VERSION 5.7 ;
  NOWIREEXTENSIONATPIN ON ;
  DIVIDERCHAR "/" ;
  BUSBITCHARS "[]" ;
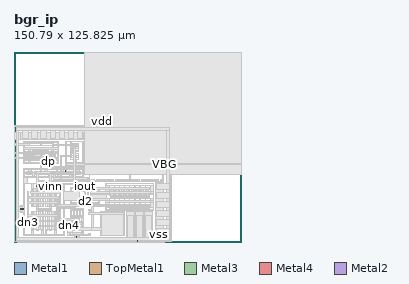
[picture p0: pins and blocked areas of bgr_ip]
MACRO bgr_ip
  CLASS BLOCK ;
  FOREIGN bgr_ip ;
  ORIGIN 58.750 13.520 ;
  SIZE 150.790 BY 125.825 ;
  PIN vss
    ANTENNAGATEAREA 13.200000 ;
    ANTENNADIFFAREA 228.791992 ;
    PORT
      LAYER Metal1 ;
        RECT 23.000 -12.945 23.300 -12.345 ;
    END
    PORT
      LAYER Metal1 ;
        RECT 30.780 -10.815 31.080 -10.215 ;
    END
    PORT
      LAYER Metal1 ;
        RECT 36.885 -10.515 37.185 -9.915 ;
    END
    PORT
      LAYER Metal1 ;
        RECT -17.380 -10.515 -17.080 -9.915 ;
    END
  END vss
  PIN vdd
    ANTENNAGATEAREA 148.000000 ;
    ANTENNADIFFAREA 272.932007 ;
    PORT
      LAYER Metal1 ;
        RECT -54.655 7.790 -52.655 8.790 ;
    END
    PORT
      LAYER TopMetal1 ;
        RECT -1.690 65.610 0.310 66.610 ;
    END
  END vdd
  PIN dn3
    ANTENNAGATEAREA 6.000000 ;
    ANTENNADIFFAREA 17.340000 ;
    PORT
      LAYER Metal1 ;
        RECT -49.535 -1.245 -49.035 -0.245 ;
    END
  END dn3
  PIN VBG
    USE ANALOG ;
    ANTENNAGATEAREA 14.400000 ;
    ANTENNADIFFAREA 11.219999 ;
    PORT
      LAYER Metal3 ;
        RECT -24.920 33.485 -24.420 33.985 ;
    END
    PORT
      LAYER Metal4 ;
        RECT 40.010 37.520 42.010 38.520 ;
    END
  END VBG
  PIN vinp
    ANTENNAGATEAREA 24.000000 ;
    ANTENNADIFFAREA 0.340000 ;
    PORT
      LAYER Metal3 ;
        RECT -43.755 23.380 -42.755 24.380 ;
    END
  END vinp
  PIN vinn
    ANTENNAGATEAREA 31.199999 ;
    ANTENNADIFFAREA 9.179999 ;
    PORT
      LAYER Metal3 ;
        RECT -34.985 22.695 -33.985 23.695 ;
    END
  END vinn
  PIN dn4
    ANTENNAGATEAREA 24.000000 ;
    ANTENNADIFFAREA 17.340000 ;
    PORT
      LAYER Metal3 ;
        RECT -22.745 -3.400 -22.245 -2.400 ;
    END
  END dn4
  PIN d2
    ANTENNADIFFAREA 36.719997 ;
    PORT
      LAYER Metal3 ;
        RECT -11.955 12.835 -11.455 13.335 ;
    END
  END d2
  PIN iout
    ANTENNAGATEAREA 324.000000 ;
    ANTENNADIFFAREA 9.120000 ;
    PORT
      LAYER Metal2 ;
        RECT -12.205 22.745 -11.205 23.245 ;
    END
  END iout
  PIN dp
    ANTENNAGATEAREA 14.400000 ;
    ANTENNADIFFAREA 11.219999 ;
    PORT
      LAYER Metal4 ;
        RECT -36.180 39.600 -35.680 40.100 ;
    END
  END dp
  PIN vout
    ANTENNAGATEAREA 22.000000 ;
    ANTENNADIFFAREA 17.080000 ;
    PORT
      LAYER Metal4 ;
        RECT -8.955 10.310 -7.955 10.810 ;
    END
  END vout
  OBS
      LAYER GatPoly ;
        RECT -7.555 57.935 -6.805 58.365 ;
        RECT -5.985 57.935 -5.235 58.365 ;
        RECT -4.415 57.935 -3.665 58.365 ;
        RECT -2.845 57.935 -2.095 58.365 ;
        RECT -1.275 57.935 -0.525 58.365 ;
        RECT 0.295 57.935 1.045 58.365 ;
        RECT 1.865 57.935 2.615 58.365 ;
        RECT 3.435 57.935 4.185 58.365 ;
        RECT 5.005 57.935 5.755 58.365 ;
        RECT 6.575 57.935 7.325 58.365 ;
        RECT 8.145 57.935 8.895 58.365 ;
        RECT 9.715 57.935 10.465 58.365 ;
        RECT 11.285 57.935 12.035 58.365 ;
        RECT 12.855 57.935 13.605 58.365 ;
        RECT 14.425 57.935 15.175 58.365 ;
        RECT 15.995 57.935 16.745 58.365 ;
        RECT 17.565 57.935 18.315 58.365 ;
        RECT 19.135 57.935 19.885 58.365 ;
        RECT 20.705 57.935 21.455 58.365 ;
        RECT 22.275 57.935 23.025 58.365 ;
        RECT 23.845 57.935 24.595 58.365 ;
        RECT 25.415 57.935 26.165 58.365 ;
        RECT 26.985 57.935 27.735 58.365 ;
        RECT 28.555 57.935 29.305 58.365 ;
        RECT 30.125 57.935 30.875 58.365 ;
        RECT 31.695 57.935 32.445 58.365 ;
        RECT 33.265 57.935 34.015 58.365 ;
        RECT 34.835 57.935 35.585 58.365 ;
        RECT 36.405 57.935 37.155 58.365 ;
        RECT 37.975 57.935 38.725 58.365 ;
        RECT -46.095 51.720 -44.095 52.020 ;
        RECT -37.875 51.720 -35.875 52.020 ;
        RECT -48.595 51.540 -41.595 51.720 ;
        RECT -40.375 51.540 -33.375 51.720 ;
        RECT -48.595 50.360 -41.595 50.540 ;
        RECT -40.375 50.360 -33.375 50.540 ;
        RECT -21.595 49.970 -21.195 50.970 ;
        RECT -16.195 50.790 -15.795 50.970 ;
        RECT -16.195 50.150 -15.715 50.790 ;
        RECT -16.195 49.970 -15.795 50.150 ;
        RECT -21.595 48.050 -21.375 49.970 ;
        RECT -16.015 48.050 -15.795 49.970 ;
        RECT -21.595 47.050 -21.195 48.050 ;
        RECT -16.195 47.050 -15.795 48.050 ;
        RECT -51.025 46.360 -50.725 46.455 ;
        RECT -41.305 46.360 -40.665 47.000 ;
        RECT -31.245 46.360 -30.945 46.455 ;
        RECT -51.025 45.910 -50.545 46.360 ;
        RECT -46.545 45.910 -46.365 46.360 ;
        RECT -45.685 45.910 -45.505 46.360 ;
        RECT -41.505 45.910 -40.465 46.360 ;
        RECT -36.465 45.910 -36.285 46.360 ;
        RECT -35.605 45.910 -35.425 46.360 ;
        RECT -31.425 45.910 -30.945 46.360 ;
        RECT -51.025 45.815 -50.725 45.910 ;
        RECT -31.245 45.815 -30.945 45.910 ;
        RECT -51.025 44.240 -50.545 44.690 ;
        RECT -46.545 44.240 -46.365 44.690 ;
        RECT -45.685 44.240 -45.505 44.690 ;
        RECT -41.505 44.240 -40.465 44.690 ;
        RECT -36.465 44.240 -36.285 44.690 ;
        RECT -35.605 44.240 -35.425 44.690 ;
        RECT -31.425 44.240 -30.945 44.690 ;
        RECT -51.025 43.020 -50.725 44.240 ;
        RECT -41.210 43.950 -40.760 44.240 ;
        RECT -41.305 43.310 -40.665 43.950 ;
        RECT -41.210 43.020 -40.760 43.310 ;
        RECT -31.245 43.020 -30.945 44.240 ;
        RECT -51.025 42.570 -50.545 43.020 ;
        RECT -46.545 42.570 -46.365 43.020 ;
        RECT -45.685 42.570 -45.505 43.020 ;
        RECT -41.505 42.570 -40.465 43.020 ;
        RECT -36.465 42.570 -36.285 43.020 ;
        RECT -35.605 42.570 -35.425 43.020 ;
        RECT -31.425 42.570 -30.945 43.020 ;
        RECT -21.595 44.130 -21.195 45.130 ;
        RECT -16.195 44.130 -15.795 45.130 ;
        RECT -21.595 43.450 -21.375 44.130 ;
        RECT -21.595 42.810 -20.525 43.450 ;
        RECT -21.595 42.210 -21.375 42.810 ;
        RECT -16.015 42.210 -15.795 44.130 ;
        RECT -7.555 43.005 -6.805 43.435 ;
        RECT -5.985 43.005 -5.235 43.435 ;
        RECT -4.415 43.005 -3.665 43.435 ;
        RECT -2.845 43.005 -2.095 43.435 ;
        RECT -1.275 43.005 -0.525 43.435 ;
        RECT 0.295 43.005 1.045 43.435 ;
        RECT 1.865 43.005 2.615 43.435 ;
        RECT 3.435 43.005 4.185 43.435 ;
        RECT 5.005 43.005 5.755 43.435 ;
        RECT 6.575 43.005 7.325 43.435 ;
        RECT 8.145 43.005 8.895 43.435 ;
        RECT 9.715 43.005 10.465 43.435 ;
        RECT 11.285 43.005 12.035 43.435 ;
        RECT 12.855 43.005 13.605 43.435 ;
        RECT 14.425 43.005 15.175 43.435 ;
        RECT 15.995 43.005 16.745 43.435 ;
        RECT 17.565 43.005 18.315 43.435 ;
        RECT 19.135 43.005 19.885 43.435 ;
        RECT 20.705 43.005 21.455 43.435 ;
        RECT 22.275 43.005 23.025 43.435 ;
        RECT 23.845 43.005 24.595 43.435 ;
        RECT 25.415 43.005 26.165 43.435 ;
        RECT 26.985 43.005 27.735 43.435 ;
        RECT 28.555 43.005 29.305 43.435 ;
        RECT 30.125 43.005 30.875 43.435 ;
        RECT 31.695 43.005 32.445 43.435 ;
        RECT 33.265 43.005 34.015 43.435 ;
        RECT 34.835 43.005 35.585 43.435 ;
        RECT 36.405 43.005 37.155 43.435 ;
        RECT 37.975 43.005 38.725 43.435 ;
        RECT -7.555 42.215 -6.805 42.645 ;
        RECT -5.985 42.215 -5.235 42.645 ;
        RECT -4.415 42.215 -3.665 42.645 ;
        RECT -2.845 42.215 -2.095 42.645 ;
        RECT -1.275 42.215 -0.525 42.645 ;
        RECT 0.295 42.215 1.045 42.645 ;
        RECT 1.865 42.215 2.615 42.645 ;
        RECT 3.435 42.215 4.185 42.645 ;
        RECT 5.005 42.215 5.755 42.645 ;
        RECT 6.575 42.215 7.325 42.645 ;
        RECT 8.145 42.215 8.895 42.645 ;
        RECT 9.715 42.215 10.465 42.645 ;
        RECT 11.285 42.215 12.035 42.645 ;
        RECT 12.855 42.215 13.605 42.645 ;
        RECT 14.425 42.215 15.175 42.645 ;
        RECT 15.995 42.215 16.745 42.645 ;
        RECT 17.565 42.215 18.315 42.645 ;
        RECT 19.135 42.215 19.885 42.645 ;
        RECT 20.705 42.215 21.455 42.645 ;
        RECT 22.275 42.215 23.025 42.645 ;
        RECT 23.845 42.215 24.595 42.645 ;
        RECT 25.415 42.215 26.165 42.645 ;
        RECT 26.985 42.215 27.735 42.645 ;
        RECT 28.555 42.215 29.305 42.645 ;
        RECT 30.125 42.215 30.875 42.645 ;
        RECT 31.695 42.215 32.445 42.645 ;
        RECT 33.265 42.215 34.015 42.645 ;
        RECT 34.835 42.215 35.585 42.645 ;
        RECT 36.405 42.215 37.155 42.645 ;
        RECT 37.975 42.215 38.725 42.645 ;
        RECT -51.025 41.350 -50.725 41.445 ;
        RECT -31.245 41.350 -30.945 41.445 ;
        RECT -51.025 40.900 -50.545 41.350 ;
        RECT -46.545 40.900 -46.365 41.350 ;
        RECT -45.685 40.900 -45.505 41.350 ;
        RECT -41.505 40.900 -40.465 41.350 ;
        RECT -36.465 40.900 -36.285 41.350 ;
        RECT -35.605 40.900 -35.425 41.350 ;
        RECT -31.425 40.900 -30.945 41.350 ;
        RECT -21.595 41.210 -21.195 42.210 ;
        RECT -16.195 41.210 -15.795 42.210 ;
        RECT -51.025 40.805 -50.725 40.900 ;
        RECT -41.305 40.260 -40.665 40.900 ;
        RECT -31.245 40.805 -30.945 40.900 ;
        RECT -49.455 32.860 -47.455 33.500 ;
        RECT -38.855 32.860 -36.855 33.500 ;
        RECT -28.255 32.860 -26.255 33.500 ;
        RECT -17.655 32.860 -15.655 33.500 ;
        RECT -50.455 32.680 -46.455 32.860 ;
        RECT -45.155 32.680 -41.155 32.860 ;
        RECT -39.855 32.680 -35.855 32.860 ;
        RECT -34.555 32.680 -30.555 32.860 ;
        RECT -29.255 32.680 -25.255 32.860 ;
        RECT -23.955 32.680 -19.955 32.860 ;
        RECT -18.655 32.680 -14.655 32.860 ;
        RECT -50.455 31.500 -46.455 31.680 ;
        RECT -45.155 31.500 -41.155 31.680 ;
        RECT -39.855 31.500 -35.855 31.680 ;
        RECT -34.555 31.500 -30.555 31.680 ;
        RECT -29.255 31.500 -25.255 31.680 ;
        RECT -23.955 31.500 -19.955 31.680 ;
        RECT -18.655 31.500 -14.655 31.680 ;
        RECT -44.155 30.860 -42.155 31.500 ;
        RECT -33.555 30.860 -31.555 31.500 ;
        RECT -22.955 30.860 -20.955 31.500 ;
        RECT -7.555 27.285 -6.805 27.715 ;
        RECT -5.985 27.285 -5.235 27.715 ;
        RECT -4.415 27.285 -3.665 27.715 ;
        RECT -2.845 27.285 -2.095 27.715 ;
        RECT -1.275 27.285 -0.525 27.715 ;
        RECT 0.295 27.285 1.045 27.715 ;
        RECT 1.865 27.285 2.615 27.715 ;
        RECT 3.435 27.285 4.185 27.715 ;
        RECT 5.005 27.285 5.755 27.715 ;
        RECT 6.575 27.285 7.325 27.715 ;
        RECT 8.145 27.285 8.895 27.715 ;
        RECT 9.715 27.285 10.465 27.715 ;
        RECT 11.285 27.285 12.035 27.715 ;
        RECT 12.855 27.285 13.605 27.715 ;
        RECT 14.425 27.285 15.175 27.715 ;
        RECT 15.995 27.285 16.745 27.715 ;
        RECT 17.565 27.285 18.315 27.715 ;
        RECT 19.135 27.285 19.885 27.715 ;
        RECT 20.705 27.285 21.455 27.715 ;
        RECT 22.275 27.285 23.025 27.715 ;
        RECT 23.845 27.285 24.595 27.715 ;
        RECT 25.415 27.285 26.165 27.715 ;
        RECT 26.985 27.285 27.735 27.715 ;
        RECT 28.555 27.285 29.305 27.715 ;
        RECT 30.125 27.285 30.875 27.715 ;
        RECT 31.695 27.285 32.445 27.715 ;
        RECT 33.265 27.285 34.015 27.715 ;
        RECT 34.835 27.285 35.585 27.715 ;
        RECT 36.405 27.285 37.155 27.715 ;
        RECT 37.975 27.285 38.725 27.715 ;
        RECT 4.615 23.640 7.615 23.820 ;
        RECT 7.995 23.640 10.995 23.820 ;
        RECT 11.375 23.640 14.375 23.820 ;
        RECT 14.755 23.640 17.755 23.820 ;
        RECT 18.135 23.640 21.135 23.820 ;
        RECT 21.515 23.640 24.515 23.820 ;
        RECT 24.895 23.640 27.895 23.820 ;
        RECT 28.275 23.640 31.275 23.820 ;
        RECT -46.645 22.095 -45.665 22.735 ;
        RECT -40.805 22.095 -39.825 22.735 ;
        RECT -37.885 22.095 -36.905 22.735 ;
        RECT -32.045 22.095 -31.065 22.735 ;
        RECT -46.655 21.915 -45.655 22.095 ;
        RECT -43.735 21.915 -42.735 22.095 ;
        RECT -40.815 21.915 -39.815 22.095 ;
        RECT -37.895 21.915 -36.895 22.095 ;
        RECT -34.975 21.915 -33.975 22.095 ;
        RECT -32.055 21.915 -31.055 22.095 ;
        RECT -12.715 20.950 -10.715 21.045 ;
        RECT -18.775 20.405 -16.775 20.705 ;
        RECT -15.235 20.405 -8.195 20.950 ;
        RECT -6.655 20.405 -4.655 20.705 ;
        RECT -19.275 20.225 -16.275 20.405 ;
        RECT -15.235 20.225 -12.235 20.405 ;
        RECT -11.195 20.225 -8.195 20.405 ;
        RECT -7.155 20.225 -4.155 20.405 ;
        RECT 4.615 17.460 7.615 17.640 ;
        RECT 7.995 17.460 10.995 17.640 ;
        RECT 11.375 17.460 14.375 17.640 ;
        RECT 14.755 17.460 17.755 17.640 ;
        RECT 18.135 17.460 21.135 17.640 ;
        RECT 21.515 17.460 24.515 17.640 ;
        RECT 24.895 17.460 27.895 17.640 ;
        RECT 28.275 17.460 31.275 17.640 ;
        RECT 5.115 16.890 7.115 17.460 ;
        RECT 8.495 16.890 10.495 17.460 ;
        RECT 11.875 16.890 13.875 17.460 ;
        RECT 15.255 16.890 17.255 17.460 ;
        RECT 18.635 16.890 20.635 17.460 ;
        RECT 22.015 16.890 24.015 17.460 ;
        RECT 25.395 16.890 27.395 17.460 ;
        RECT 28.775 16.890 30.775 17.460 ;
        RECT 5.115 15.230 7.115 15.870 ;
        RECT 8.495 15.230 10.495 15.870 ;
        RECT 11.875 15.230 13.875 15.870 ;
        RECT 15.255 15.230 17.255 15.870 ;
        RECT 18.635 15.230 20.635 15.870 ;
        RECT 22.015 15.230 24.015 15.870 ;
        RECT 25.395 15.230 27.395 15.870 ;
        RECT 28.775 15.230 30.775 15.870 ;
        RECT 4.615 15.050 7.615 15.230 ;
        RECT 7.995 15.050 10.995 15.230 ;
        RECT 11.375 15.050 14.375 15.230 ;
        RECT 14.755 15.050 17.755 15.230 ;
        RECT 18.135 15.050 21.135 15.230 ;
        RECT 21.515 15.050 24.515 15.230 ;
        RECT 24.895 15.050 27.895 15.230 ;
        RECT 28.275 15.050 31.275 15.230 ;
        RECT -19.275 14.045 -16.275 14.225 ;
        RECT -15.235 14.045 -12.235 14.225 ;
        RECT -11.195 14.045 -8.195 14.225 ;
        RECT -7.155 14.045 -4.155 14.225 ;
        RECT -18.775 13.745 -16.775 14.045 ;
        RECT -15.235 13.500 -8.195 14.045 ;
        RECT -6.655 13.745 -4.655 14.045 ;
        RECT -46.655 9.735 -45.655 9.915 ;
        RECT -43.735 9.735 -42.735 9.915 ;
        RECT -40.815 9.735 -39.815 9.915 ;
        RECT -37.895 9.735 -36.895 9.915 ;
        RECT -34.975 9.735 -33.975 9.915 ;
        RECT -32.055 9.735 -31.055 9.915 ;
        RECT -43.725 9.095 -42.745 9.735 ;
        RECT -34.965 9.095 -33.985 9.735 ;
        RECT 4.615 8.870 7.615 9.050 ;
        RECT 7.995 8.870 10.995 9.050 ;
        RECT 11.375 8.870 14.375 9.050 ;
        RECT 14.755 8.870 17.755 9.050 ;
        RECT 18.135 8.870 21.135 9.050 ;
        RECT 21.515 8.870 24.515 9.050 ;
        RECT 24.895 8.870 27.895 9.050 ;
        RECT 28.275 8.870 31.275 9.050 ;
        RECT -20.425 7.315 -19.445 7.615 ;
        RECT -18.530 7.570 -17.890 7.590 ;
        RECT -18.530 7.315 -15.640 7.570 ;
        RECT -14.725 7.315 -13.745 7.615 ;
        RECT -9.090 7.430 -8.090 7.860 ;
        RECT -43.725 6.645 -42.745 7.285 ;
        RECT -34.965 6.645 -33.985 7.285 ;
        RECT -20.435 7.135 -19.435 7.315 ;
        RECT -18.530 7.135 -17.530 7.315 ;
        RECT -16.640 7.135 -15.640 7.315 ;
        RECT -14.735 7.135 -13.735 7.315 ;
        RECT -46.655 6.465 -45.655 6.645 ;
        RECT -43.735 6.465 -42.735 6.645 ;
        RECT -40.815 6.465 -39.815 6.645 ;
        RECT -37.895 6.465 -36.895 6.645 ;
        RECT -34.975 6.465 -33.975 6.645 ;
        RECT -32.055 6.465 -31.055 6.645 ;
        RECT -20.435 3.955 -19.435 4.135 ;
        RECT -18.530 3.955 -17.530 4.135 ;
        RECT -16.640 3.955 -15.640 4.135 ;
        RECT -14.735 3.955 -13.735 4.135 ;
        RECT -20.425 3.655 -19.445 3.955 ;
        RECT -18.530 3.700 -15.640 3.955 ;
        RECT -14.725 3.655 -13.745 3.955 ;
        RECT -20.265 -2.180 -20.085 -2.170 ;
        RECT -20.905 -3.160 -20.085 -2.180 ;
        RECT -20.265 -3.170 -20.085 -3.160 ;
        RECT -14.085 -3.170 -13.905 -2.170 ;
        RECT -20.265 -3.560 -20.085 -3.550 ;
        RECT -20.905 -4.540 -20.085 -3.560 ;
        RECT -20.265 -4.550 -20.085 -4.540 ;
        RECT -14.085 -4.550 -13.905 -3.550 ;
        RECT -20.265 -4.940 -20.085 -4.930 ;
        RECT -46.655 -5.715 -45.655 -5.535 ;
        RECT -43.735 -5.715 -42.735 -5.535 ;
        RECT -40.815 -5.715 -39.815 -5.535 ;
        RECT -37.895 -5.715 -36.895 -5.535 ;
        RECT -34.975 -5.715 -33.975 -5.535 ;
        RECT -32.055 -5.715 -31.055 -5.535 ;
        RECT -46.645 -6.355 -45.665 -5.715 ;
        RECT -40.805 -6.355 -39.825 -5.715 ;
        RECT -37.885 -6.355 -36.905 -5.715 ;
        RECT -32.045 -6.355 -31.065 -5.715 ;
        RECT -20.905 -5.920 -20.085 -4.940 ;
        RECT -20.265 -5.930 -20.085 -5.920 ;
        RECT -14.085 -5.930 -13.905 -4.930 ;
        RECT -20.265 -6.320 -20.085 -6.310 ;
        RECT -20.905 -7.300 -20.085 -6.320 ;
        RECT -20.265 -7.310 -20.085 -7.300 ;
        RECT -14.085 -7.310 -13.905 -6.310 ;
        RECT -9.090 -8.000 -8.090 -7.570 ;
      LAYER Metal1 ;
        RECT -58.750 62.785 45.370 63.445 ;
        RECT -58.750 59.055 -58.130 62.785 ;
        RECT -58.750 54.255 -53.595 59.055 ;
        RECT -9.050 58.925 39.950 59.225 ;
        RECT -58.750 51.540 -58.130 54.255 ;
        RECT -52.545 52.690 -29.425 53.290 ;
        RECT -52.545 51.540 -52.045 52.690 ;
        RECT -46.265 51.720 -40.485 52.110 ;
        RECT -37.855 51.790 -32.645 52.110 ;
        RECT -58.750 50.540 -48.705 51.540 ;
        RECT -41.485 50.540 -40.485 51.720 ;
        RECT -58.750 45.800 -58.130 50.540 ;
        RECT -52.545 49.390 -52.045 50.540 ;
        RECT -33.265 49.925 -32.645 51.790 ;
        RECT -29.925 49.390 -29.425 52.690 ;
        RECT -52.545 48.010 -29.425 49.390 ;
        RECT -52.545 45.800 -52.045 48.010 ;
        RECT -49.365 46.700 -47.725 48.010 ;
        RECT -51.065 46.470 -46.545 46.700 ;
        RECT -51.065 45.800 -50.725 46.470 ;
        RECT -46.330 46.380 -35.640 46.980 ;
        RECT -34.245 46.700 -32.395 48.010 ;
        RECT -35.425 46.470 -30.905 46.700 ;
        RECT -31.245 45.800 -30.905 46.470 ;
        RECT -29.925 45.800 -29.425 48.010 ;
        RECT -58.750 44.800 -29.425 45.800 ;
        RECT -58.750 42.460 -58.130 44.800 ;
        RECT -52.545 42.460 -52.045 44.800 ;
        RECT -50.545 43.970 -46.545 44.130 ;
        RECT -46.335 43.970 -45.715 43.980 ;
        RECT -51.025 43.290 -45.715 43.970 ;
        RECT -50.545 43.130 -46.545 43.290 ;
        RECT -46.335 43.280 -45.715 43.290 ;
        RECT -45.505 43.130 -36.465 44.130 ;
        RECT -36.255 43.970 -35.635 43.980 ;
        RECT -35.425 43.970 -31.425 44.130 ;
        RECT -36.255 43.290 -30.945 43.970 ;
        RECT -36.255 43.280 -31.425 43.290 ;
        RECT -35.425 43.130 -31.425 43.280 ;
        RECT -29.925 42.460 -29.425 44.800 ;
        RECT -58.750 41.460 -29.425 42.460 ;
        RECT -58.750 -12.895 -58.130 41.460 ;
        RECT -52.545 39.250 -52.045 41.460 ;
        RECT -51.065 40.790 -50.725 41.460 ;
        RECT -51.065 40.560 -46.545 40.790 ;
        RECT -49.365 39.250 -47.725 40.560 ;
        RECT -46.330 40.280 -35.640 40.880 ;
        RECT -31.245 40.790 -30.905 41.460 ;
        RECT -35.425 40.560 -30.905 40.790 ;
        RECT -34.260 39.250 -32.395 40.560 ;
        RECT -29.925 39.250 -29.425 41.460 ;
        RECT -52.545 38.650 -29.425 39.250 ;
        RECT -24.665 52.770 -12.725 53.270 ;
        RECT -24.665 39.410 -24.065 52.770 ;
        RECT -21.195 51.490 -20.495 52.240 ;
        RECT -21.195 51.080 -16.195 51.490 ;
        RECT -15.970 50.120 -15.760 50.820 ;
        RECT -21.195 48.160 -16.195 49.860 ;
        RECT -21.195 46.530 -16.195 46.940 ;
        RECT -21.195 45.985 -20.495 46.530 ;
        RECT -20.145 45.400 -19.445 46.195 ;
        RECT -21.195 45.240 -16.195 45.400 ;
        RECT -21.195 43.860 -16.195 44.020 ;
        RECT -21.195 42.820 -20.495 43.440 ;
        RECT -19.520 42.480 -17.510 43.860 ;
        RECT -21.195 42.320 -16.195 42.480 ;
        RECT -21.195 40.940 -16.195 41.100 ;
        RECT -19.520 39.410 -17.510 40.940 ;
        RECT -13.325 39.410 -12.725 52.770 ;
        RECT -24.665 38.910 -12.725 39.410 ;
        RECT -24.615 35.000 -21.595 38.910 ;
        RECT -15.795 35.000 -12.775 38.910 ;
        RECT -52.335 34.400 -12.775 35.000 ;
        RECT -52.335 32.680 -51.835 34.400 ;
        RECT -49.435 32.930 -47.475 34.400 ;
        RECT -38.835 33.430 -36.875 34.400 ;
        RECT -30.555 33.430 -29.775 34.400 ;
        RECT -28.235 33.430 -26.275 34.400 ;
        RECT -52.335 31.680 -50.565 32.680 ;
        RECT -52.335 29.960 -51.835 31.680 ;
        RECT -46.345 29.960 -45.265 32.680 ;
        RECT -41.275 31.680 -40.655 33.085 ;
        RECT -40.375 32.930 -35.335 33.430 ;
        RECT -40.375 31.680 -39.855 32.930 ;
        RECT -44.325 30.870 -41.985 31.490 ;
        RECT -35.855 29.960 -35.335 32.930 ;
        RECT -35.055 31.975 -34.435 33.085 ;
        RECT -35.050 31.680 -34.435 31.975 ;
        RECT -30.555 32.930 -24.735 33.430 ;
        RECT -30.555 31.680 -29.255 32.930 ;
        RECT -25.255 31.685 -24.735 32.930 ;
        RECT -25.145 31.680 -24.985 31.685 ;
        RECT -24.455 31.680 -23.835 33.085 ;
        RECT -17.635 32.930 -15.675 34.400 ;
        RECT -13.275 32.680 -12.775 34.400 ;
        RECT -33.725 30.870 -31.385 31.490 ;
        RECT -29.775 29.960 -29.255 31.680 ;
        RECT -23.125 30.870 -20.785 31.490 ;
        RECT -19.845 29.960 -18.765 32.680 ;
        RECT -14.545 31.680 -12.775 32.680 ;
        RECT -13.275 29.960 -12.775 31.680 ;
        RECT -52.335 29.360 -12.775 29.960 ;
        RECT -52.335 25.500 -50.075 29.360 ;
        RECT -9.050 26.525 -8.750 58.925 ;
        RECT -7.535 57.435 -6.825 58.545 ;
        RECT -5.965 58.065 -3.685 58.365 ;
        RECT -2.825 58.065 -0.545 58.365 ;
        RECT 0.315 58.065 2.595 58.365 ;
        RECT 3.455 58.065 5.735 58.365 ;
        RECT 6.595 58.065 8.875 58.365 ;
        RECT 9.735 58.065 12.015 58.365 ;
        RECT 12.875 58.065 15.155 58.365 ;
        RECT 16.015 58.065 16.725 58.925 ;
        RECT 17.585 58.065 19.865 58.365 ;
        RECT 20.725 58.065 23.005 58.365 ;
        RECT 23.865 58.065 26.145 58.365 ;
        RECT 27.005 58.065 29.285 58.365 ;
        RECT 30.145 58.065 32.425 58.365 ;
        RECT 33.285 58.065 35.565 58.365 ;
        RECT 36.425 58.065 38.705 58.365 ;
        RECT 39.650 55.400 39.950 58.925 ;
        RECT 44.750 55.400 45.370 62.785 ;
        RECT 39.650 52.495 45.370 55.400 ;
        RECT -7.535 42.345 -6.825 43.305 ;
        RECT -5.965 42.345 -5.255 43.305 ;
        RECT -4.395 42.345 -3.685 43.305 ;
        RECT -2.825 42.345 -2.115 43.305 ;
        RECT -1.255 42.345 -0.545 43.305 ;
        RECT 0.315 42.345 1.025 43.305 ;
        RECT 1.885 42.345 2.595 43.305 ;
        RECT 3.455 42.345 4.165 43.305 ;
        RECT 5.025 42.345 5.735 43.305 ;
        RECT 6.595 42.345 7.305 43.305 ;
        RECT 8.165 42.345 8.875 43.305 ;
        RECT 9.735 42.345 10.445 43.305 ;
        RECT 11.305 42.345 12.015 43.305 ;
        RECT 12.875 42.345 13.585 43.305 ;
        RECT 14.445 42.345 15.155 43.305 ;
        RECT 16.015 42.345 16.725 43.305 ;
        RECT 17.585 42.345 18.295 43.305 ;
        RECT 19.155 42.345 19.865 43.305 ;
        RECT 20.725 42.345 21.435 43.305 ;
        RECT 22.295 42.345 23.005 43.305 ;
        RECT 23.865 42.345 24.575 43.305 ;
        RECT 25.435 42.345 26.145 43.305 ;
        RECT 27.005 42.345 27.715 43.305 ;
        RECT 28.575 42.345 29.285 43.305 ;
        RECT 30.145 42.345 30.855 43.305 ;
        RECT 31.715 42.345 32.425 43.305 ;
        RECT 33.285 42.345 33.995 43.305 ;
        RECT 34.855 42.345 35.565 43.305 ;
        RECT 36.425 42.345 37.135 43.305 ;
        RECT 37.995 42.345 38.705 43.305 ;
        RECT 17.185 37.330 18.295 38.360 ;
        RECT -7.535 27.285 -5.255 27.585 ;
        RECT -4.395 26.890 -2.115 27.585 ;
        RECT -1.255 27.285 1.025 27.585 ;
        RECT 1.885 27.285 4.165 27.585 ;
        RECT 5.025 27.285 7.305 27.585 ;
        RECT 8.165 27.285 10.445 27.585 ;
        RECT 11.305 27.285 13.585 27.585 ;
        RECT 14.445 27.285 16.725 27.585 ;
        RECT 17.585 27.285 18.295 37.330 ;
        RECT 39.650 34.240 39.950 52.495 ;
        RECT 44.750 34.240 45.370 52.495 ;
        RECT 39.650 31.415 45.370 34.240 ;
        RECT 39.650 27.585 39.950 31.415 ;
        RECT 19.155 27.285 21.435 27.585 ;
        RECT 22.295 27.285 24.575 27.585 ;
        RECT 25.435 27.285 27.715 27.585 ;
        RECT 28.575 27.285 30.855 27.585 ;
        RECT 31.715 27.285 33.995 27.585 ;
        RECT 34.855 27.285 37.135 27.585 ;
        RECT 37.995 27.285 39.950 27.585 ;
        RECT -3.810 26.885 -2.700 26.890 ;
        RECT 39.650 26.525 39.950 27.285 ;
        RECT -9.050 26.225 39.950 26.525 ;
        RECT -52.335 24.900 -25.375 25.500 ;
        RECT -52.335 10.380 -51.835 24.900 ;
        RECT -46.925 22.165 -45.685 24.900 ;
        RECT -43.990 22.535 -42.470 23.155 ;
        RECT -54.655 8.790 -51.835 10.380 ;
        RECT -52.655 7.790 -51.835 8.790 ;
        RECT -54.655 6.000 -51.835 7.790 ;
        RECT -52.335 -8.520 -51.835 6.000 ;
        RECT -49.595 13.025 -48.975 19.910 ;
        RECT -49.595 11.915 -48.970 13.025 ;
        RECT -49.595 4.460 -48.975 11.915 ;
        RECT -46.925 9.915 -46.625 22.165 ;
        RECT -45.545 9.915 -43.845 21.915 ;
        RECT -43.535 9.665 -42.935 22.535 ;
        RECT -40.785 22.165 -39.545 24.900 ;
        RECT -42.625 9.915 -40.925 21.915 ;
        RECT -39.845 9.915 -39.545 22.165 ;
        RECT -38.165 22.165 -36.925 24.900 ;
        RECT -35.230 22.530 -33.710 23.150 ;
        RECT -38.165 9.915 -37.865 22.165 ;
        RECT -36.785 9.915 -35.085 21.915 ;
        RECT -34.775 9.725 -34.175 22.530 ;
        RECT -32.025 22.165 -30.785 24.900 ;
        RECT -33.865 9.915 -32.165 21.915 ;
        RECT -31.085 9.915 -30.785 22.165 ;
        RECT -25.875 20.225 -25.375 24.900 ;
        RECT 1.945 24.900 33.945 25.500 ;
        RECT 1.945 23.710 2.445 24.900 ;
        RECT 33.445 23.710 33.945 24.900 ;
        RECT -21.415 21.965 -2.015 22.565 ;
        RECT -21.415 20.225 -20.915 21.965 ;
        RECT -18.755 20.225 -16.795 20.635 ;
        RECT -12.885 20.415 -10.545 21.035 ;
        RECT -6.635 20.225 -4.675 20.635 ;
        RECT -2.515 20.225 -2.015 21.965 ;
        RECT 1.945 20.225 4.505 23.710 ;
        RECT 7.725 22.895 7.885 23.640 ;
        RECT -28.740 18.800 -28.115 19.910 ;
        RECT -43.790 7.475 -42.680 9.665 ;
        RECT -35.030 9.105 -33.920 9.725 ;
        RECT -43.790 6.655 -42.680 7.275 ;
        RECT -35.030 6.715 -33.920 8.885 ;
        RECT -49.595 3.350 -48.970 4.460 ;
        RECT -49.595 -0.245 -48.975 3.350 ;
        RECT -49.595 -1.245 -49.535 -0.245 ;
        RECT -49.035 -1.245 -48.975 -0.245 ;
        RECT -49.595 -3.535 -48.975 -1.245 ;
        RECT -46.925 -5.785 -46.625 6.465 ;
        RECT -45.545 -5.535 -43.845 6.465 ;
        RECT -42.625 -5.535 -40.925 6.465 ;
        RECT -39.845 -5.785 -39.545 6.465 ;
        RECT -46.925 -8.520 -45.685 -5.785 ;
        RECT -40.785 -8.520 -39.545 -5.785 ;
        RECT -38.165 -5.785 -37.865 6.465 ;
        RECT -36.785 -5.535 -35.085 6.465 ;
        RECT -33.865 -5.535 -32.165 6.465 ;
        RECT -31.085 -5.785 -30.785 6.465 ;
        RECT -28.740 1.995 -28.120 18.800 ;
        RECT -25.875 14.225 -15.345 20.225 ;
        RECT -12.125 18.395 -11.305 20.225 ;
        RECT -8.085 20.045 4.505 20.225 ;
        RECT -8.085 18.525 4.530 20.045 ;
        RECT -12.230 16.055 -11.200 18.395 ;
        RECT -8.085 17.710 4.505 18.525 ;
        RECT -12.125 14.225 -11.305 16.055 ;
        RECT -8.085 15.050 2.445 17.710 ;
        RECT 4.345 17.640 4.505 17.710 ;
        RECT 5.355 17.460 6.875 22.445 ;
        RECT 7.700 21.375 7.910 22.895 ;
        RECT 7.725 17.640 7.885 21.375 ;
        RECT 8.735 17.460 10.255 22.445 ;
        RECT 11.105 20.045 11.265 23.640 ;
        RECT 14.485 22.895 14.645 23.640 ;
        RECT 11.080 18.525 11.290 20.045 ;
        RECT 11.105 17.640 11.265 18.525 ;
        RECT 12.115 17.460 13.635 22.445 ;
        RECT 14.460 21.375 14.670 22.895 ;
        RECT 14.485 17.640 14.645 21.375 ;
        RECT 15.495 17.460 17.015 22.445 ;
        RECT 17.865 20.045 18.025 23.640 ;
        RECT 21.245 22.895 21.405 23.640 ;
        RECT 17.840 18.525 18.050 20.045 ;
        RECT 17.865 17.640 18.025 18.525 ;
        RECT 18.875 17.460 20.395 22.445 ;
        RECT 21.220 21.375 21.430 22.895 ;
        RECT 21.245 17.640 21.405 21.375 ;
        RECT 22.255 17.460 23.775 22.445 ;
        RECT 24.625 20.045 24.785 23.640 ;
        RECT 28.005 22.895 28.165 23.640 ;
        RECT 24.600 18.525 24.810 20.045 ;
        RECT 24.625 17.640 24.785 18.525 ;
        RECT 25.635 17.460 27.155 22.445 ;
        RECT 27.980 21.375 28.190 22.895 ;
        RECT 28.005 17.640 28.165 21.375 ;
        RECT 29.015 17.460 30.535 22.445 ;
        RECT 31.385 20.045 33.945 23.710 ;
        RECT 31.360 18.525 33.945 20.045 ;
        RECT 31.385 17.710 33.945 18.525 ;
        RECT 31.385 17.640 31.545 17.710 ;
        RECT 5.135 15.300 7.095 17.460 ;
        RECT 8.515 15.300 10.475 17.460 ;
        RECT 11.895 15.300 13.855 17.460 ;
        RECT 15.275 15.300 17.235 17.460 ;
        RECT 18.655 15.300 20.615 17.460 ;
        RECT 22.035 15.300 23.995 17.460 ;
        RECT 25.415 15.300 27.375 17.460 ;
        RECT 28.795 15.300 30.755 17.460 ;
        RECT 33.445 15.050 33.945 17.710 ;
        RECT -8.085 14.235 4.505 15.050 ;
        RECT -8.085 14.225 4.530 14.235 ;
        RECT -28.740 0.885 -28.115 1.995 ;
        RECT -28.740 -2.425 -28.120 0.885 ;
        RECT -28.740 -3.535 -28.115 -2.425 ;
        RECT -38.165 -8.520 -36.925 -5.785 ;
        RECT -32.025 -8.520 -30.785 -5.785 ;
        RECT -25.875 -8.520 -25.375 14.225 ;
        RECT -21.415 12.485 -20.915 14.225 ;
        RECT -18.755 13.815 -16.795 14.225 ;
        RECT -6.635 13.815 -4.675 14.225 ;
        RECT -2.515 12.485 -2.015 14.225 ;
        RECT -21.415 11.885 -2.015 12.485 ;
        RECT 1.945 12.715 4.530 14.225 ;
        RECT 1.945 9.050 4.505 12.715 ;
        RECT 7.725 11.385 7.885 15.050 ;
        RECT 11.105 14.235 11.265 15.050 ;
        RECT 11.080 12.715 11.290 14.235 ;
        RECT 7.700 9.865 7.910 11.385 ;
        RECT 7.725 9.050 7.885 9.865 ;
        RECT 11.105 9.050 11.265 12.715 ;
        RECT 14.485 11.385 14.645 15.050 ;
        RECT 17.865 14.235 18.025 15.050 ;
        RECT 17.840 12.715 18.050 14.235 ;
        RECT 14.460 9.865 14.670 11.385 ;
        RECT 14.485 9.050 14.645 9.865 ;
        RECT 17.865 9.050 18.025 12.715 ;
        RECT 21.245 11.385 21.405 15.050 ;
        RECT 24.625 14.235 24.785 15.050 ;
        RECT 24.600 12.715 24.810 14.235 ;
        RECT 21.220 9.865 21.430 11.385 ;
        RECT 21.245 9.050 21.405 9.865 ;
        RECT 24.625 9.050 24.785 12.715 ;
        RECT 28.005 11.385 28.165 15.050 ;
        RECT 31.385 14.235 33.945 15.050 ;
        RECT 31.360 12.715 33.945 14.235 ;
        RECT 27.980 9.865 28.190 11.385 ;
        RECT 28.005 9.050 28.165 9.865 ;
        RECT 31.385 9.050 33.945 12.715 ;
        RECT -21.625 8.065 -12.545 8.665 ;
        RECT -21.625 3.205 -21.125 8.065 ;
        RECT -20.405 7.545 -19.465 8.065 ;
        RECT -20.705 7.385 -19.165 7.545 ;
        RECT -20.705 3.885 -20.545 7.385 ;
        RECT -19.325 3.885 -19.165 7.385 ;
        RECT -18.560 7.335 -17.860 7.545 ;
        RECT -18.800 6.805 -18.640 7.135 ;
        RECT -18.825 4.465 -18.615 6.805 ;
        RECT -18.800 4.135 -18.640 4.465 ;
        RECT -20.705 3.725 -19.165 3.885 ;
        RECT -20.405 3.205 -19.465 3.725 ;
        RECT -17.420 3.205 -16.750 8.065 ;
        RECT -14.705 7.545 -13.765 8.065 ;
        RECT -15.005 7.385 -13.465 7.545 ;
        RECT -15.530 6.805 -15.370 7.135 ;
        RECT -15.555 4.465 -15.345 6.805 ;
        RECT -15.530 4.135 -15.370 4.465 ;
        RECT -16.340 3.725 -15.640 3.935 ;
        RECT -15.005 3.885 -14.845 7.385 ;
        RECT -13.625 3.885 -13.465 7.385 ;
        RECT -15.005 3.725 -13.465 3.885 ;
        RECT -14.705 3.205 -13.765 3.725 ;
        RECT -13.045 3.205 -12.545 8.065 ;
        RECT -9.070 5.200 -8.110 8.080 ;
        RECT 1.945 7.860 2.445 9.050 ;
        RECT 33.445 7.860 33.945 9.050 ;
        RECT 1.945 7.260 33.945 7.860 ;
        RECT -8.940 5.080 -8.240 5.200 ;
        RECT -21.625 2.605 -12.545 3.205 ;
        RECT -14.180 -0.200 -12.545 2.605 ;
        RECT -52.335 -9.120 -25.375 -8.520 ;
        RECT -21.675 -0.700 -12.495 -0.200 ;
        RECT -21.675 -8.780 -21.075 -0.700 ;
        RECT -20.085 -2.060 -14.085 -0.700 ;
        RECT -20.895 -3.225 -20.275 -2.115 ;
        RECT -18.255 -3.280 -15.915 -3.255 ;
        RECT -20.085 -3.440 -14.085 -3.280 ;
        RECT -18.255 -3.465 -15.915 -3.440 ;
        RECT -20.895 -4.605 -20.275 -3.495 ;
        RECT -13.095 -4.600 -12.495 -0.700 ;
        RECT -20.895 -5.985 -20.275 -4.875 ;
        RECT -20.085 -4.880 -12.495 -4.600 ;
        RECT -18.255 -6.040 -15.915 -6.015 ;
        RECT -20.085 -6.200 -14.085 -6.040 ;
        RECT -18.255 -6.225 -15.915 -6.200 ;
        RECT -20.895 -7.365 -20.275 -6.255 ;
        RECT -20.085 -8.780 -14.085 -7.420 ;
        RECT -13.095 -8.780 -12.495 -4.880 ;
        RECT -21.675 -9.280 -12.495 -8.780 ;
        RECT -18.555 -9.915 -15.615 -9.280 ;
        RECT -9.270 -9.450 -7.910 -7.700 ;
        RECT -18.555 -10.515 -17.380 -9.915 ;
        RECT -17.080 -10.515 -15.615 -9.915 ;
        RECT -18.555 -12.895 -15.615 -10.515 ;
        RECT 15.800 -12.895 20.600 -9.610 ;
        RECT 21.980 -12.345 26.780 -9.610 ;
        RECT 21.980 -12.895 23.000 -12.345 ;
        RECT -58.750 -12.945 23.000 -12.895 ;
        RECT 23.300 -12.895 26.780 -12.345 ;
        RECT 28.170 -10.215 32.970 -9.440 ;
        RECT 28.170 -10.815 30.780 -10.215 ;
        RECT 31.080 -10.815 32.970 -10.215 ;
        RECT 28.170 -12.895 32.970 -10.815 ;
        RECT 34.980 -9.915 39.780 -9.450 ;
        RECT 34.980 -10.515 36.885 -9.915 ;
        RECT 37.185 -10.515 39.780 -9.915 ;
        RECT 34.980 -12.895 39.780 -10.515 ;
        RECT 44.750 -12.895 45.370 31.415 ;
        RECT 23.300 -12.945 45.370 -12.895 ;
        RECT -58.750 -13.515 45.370 -12.945 ;
        RECT -56.620 -13.520 40.920 -13.515 ;
      LAYER Metal2 ;
        RECT -58.745 62.790 45.365 63.445 ;
        RECT -58.745 -12.900 -58.135 62.790 ;
        RECT -54.210 54.255 -53.600 59.055 ;
        RECT -7.440 57.435 -6.830 58.545 ;
        RECT -33.260 49.925 -32.650 51.035 ;
        RECT -46.330 46.965 -45.720 46.970 ;
        RECT -36.250 46.965 -35.640 46.970 ;
        RECT -46.330 46.765 -45.630 46.965 ;
        RECT -36.340 46.765 -35.640 46.965 ;
        RECT -46.330 40.495 -45.720 46.765 ;
        RECT -41.290 43.280 -40.680 43.980 ;
        RECT -36.250 40.495 -35.640 46.765 ;
        RECT -21.195 43.435 -20.495 52.235 ;
        RECT -20.145 50.165 -18.345 50.775 ;
        RECT -20.145 45.785 -19.445 50.165 ;
        RECT -16.015 50.120 -15.765 50.820 ;
        RECT -19.045 48.705 -18.345 49.315 ;
        RECT -28.110 42.825 -20.495 43.435 ;
        RECT -46.330 40.295 -45.630 40.495 ;
        RECT -36.340 40.295 -35.640 40.495 ;
        RECT -46.330 40.290 -45.720 40.295 ;
        RECT -36.250 40.290 -35.640 40.295 ;
        RECT -24.920 37.345 18.315 38.360 ;
        RECT -24.920 37.340 -23.810 37.345 ;
        RECT 17.185 37.335 18.295 37.345 ;
        RECT -36.250 35.580 -9.965 36.690 ;
        RECT -41.270 31.975 -40.660 33.085 ;
        RECT -35.050 31.975 -34.440 33.085 ;
        RECT -24.450 31.975 -23.840 33.085 ;
        RECT -44.325 30.875 -20.785 31.485 ;
        RECT -32.430 29.025 -31.385 30.875 ;
        RECT -21.850 29.025 -20.785 30.875 ;
        RECT -32.430 27.915 -9.320 29.025 ;
        RECT -43.995 26.435 -2.700 27.500 ;
        RECT -16.170 25.860 -16.160 25.870 ;
        RECT -35.230 24.260 -18.345 25.370 ;
        RECT -12.970 23.245 -10.630 23.375 ;
        RECT -43.990 22.540 -42.470 23.150 ;
        RECT -35.230 22.535 -33.710 23.145 ;
        RECT -12.970 22.745 -12.205 23.245 ;
        RECT -11.205 22.745 -10.630 23.245 ;
        RECT -12.970 21.030 -10.630 22.745 ;
        RECT 5.355 21.830 6.875 22.440 ;
        RECT 7.705 21.375 7.905 22.895 ;
        RECT 8.735 21.830 10.255 22.440 ;
        RECT 12.115 21.830 13.635 22.440 ;
        RECT 14.465 21.375 14.665 22.895 ;
        RECT 15.495 21.830 17.015 22.440 ;
        RECT 18.875 21.830 20.395 22.440 ;
        RECT 21.225 21.375 21.425 22.895 ;
        RECT 22.255 21.830 23.775 22.440 ;
        RECT 25.635 21.830 27.155 22.440 ;
        RECT 27.985 21.375 28.185 22.895 ;
        RECT 29.015 21.830 30.535 22.440 ;
        RECT -12.970 20.420 -10.545 21.030 ;
        RECT -47.615 18.800 -28.120 19.910 ;
        RECT 4.325 18.525 31.565 20.045 ;
        RECT -45.000 15.360 -44.390 16.470 ;
        RECT -36.240 15.360 -35.630 16.470 ;
        RECT -12.225 16.055 -11.205 18.395 ;
        RECT 5.355 16.075 30.535 16.685 ;
        RECT -49.590 11.915 -30.090 13.025 ;
        RECT 4.325 12.715 31.565 14.235 ;
        RECT -53.440 8.985 -52.830 10.095 ;
        RECT -35.030 9.110 -33.920 9.720 ;
        RECT -53.440 6.465 -52.830 7.575 ;
        RECT -43.790 7.480 -33.920 8.090 ;
        RECT -43.790 6.660 -42.680 7.270 ;
        RECT -30.700 4.460 -30.090 11.915 ;
        RECT -29.840 10.220 -11.205 11.330 ;
        RECT 7.705 9.865 7.905 11.385 ;
        RECT 14.465 9.865 14.665 11.385 ;
        RECT 21.225 9.865 21.425 11.385 ;
        RECT 27.985 9.865 28.185 11.385 ;
        RECT -18.530 7.540 -17.860 7.590 ;
        RECT -18.560 7.340 -17.860 7.540 ;
        RECT -18.530 7.335 -17.860 7.340 ;
        RECT -18.820 4.465 -18.620 6.805 ;
        RECT -15.550 4.465 -15.350 6.805 ;
        RECT -8.940 5.085 -8.240 5.695 ;
        RECT -49.590 3.350 -30.090 4.460 ;
        RECT -16.340 3.700 -15.640 3.935 ;
        RECT -45.000 -0.090 -44.390 1.020 ;
        RECT -36.240 -0.090 -35.630 1.020 ;
        RECT -28.730 0.885 -15.350 1.995 ;
        RECT -47.615 -3.535 -28.120 -2.425 ;
        RECT -20.890 -3.225 -20.280 -2.115 ;
        RECT -20.890 -4.605 -20.280 -3.495 ;
        RECT -20.890 -5.985 -20.280 -4.875 ;
        RECT -18.255 -6.220 -15.915 -3.260 ;
        RECT -20.890 -7.365 -20.280 -6.255 ;
        RECT -23.080 -9.450 -8.110 -8.670 ;
        RECT 15.800 -10.225 20.600 -9.615 ;
        RECT 21.980 -10.225 26.780 -9.615 ;
        RECT 28.170 -10.055 32.970 -9.445 ;
        RECT 34.980 -10.065 39.780 -9.455 ;
        RECT 44.755 -12.900 45.365 62.790 ;
        RECT -58.745 -13.515 45.365 -12.900 ;
      LAYER Metal3 ;
        RECT -54.210 54.255 -53.600 59.055 ;
        RECT -10.865 57.435 -6.825 58.545 ;
        RECT -33.260 50.775 -32.650 51.035 ;
        RECT -15.965 50.775 -15.765 50.820 ;
        RECT -33.260 50.165 -15.765 50.775 ;
        RECT -33.260 49.925 -32.650 50.165 ;
        RECT -15.965 50.120 -15.765 50.165 ;
        RECT -19.045 48.705 -18.345 49.315 ;
        RECT -41.290 43.280 -40.680 43.980 ;
        RECT -36.250 43.280 -35.640 43.980 ;
        RECT -28.110 42.825 -27.410 43.435 ;
        RECT -24.920 37.340 -23.810 38.360 ;
        RECT -36.250 35.580 -35.640 36.690 ;
        RECT -24.920 33.985 -23.840 37.340 ;
        RECT 17.185 37.335 18.295 38.355 ;
        RECT -10.575 35.580 -9.965 36.690 ;
        RECT -24.420 33.485 -23.840 33.985 ;
        RECT -43.990 33.080 -40.660 33.085 ;
        RECT -43.995 31.975 -40.660 33.080 ;
        RECT -43.995 24.380 -42.475 31.975 ;
        RECT -43.995 23.380 -43.755 24.380 ;
        RECT -42.755 23.380 -42.475 24.380 ;
        RECT -43.995 23.150 -42.475 23.380 ;
        RECT -35.230 23.695 -33.710 33.085 ;
        RECT -24.920 31.975 -23.840 33.485 ;
        RECT -28.110 28.050 -27.410 28.660 ;
        RECT -18.955 24.260 -18.345 25.370 ;
        RECT -43.995 22.540 -42.470 23.150 ;
        RECT -35.230 22.695 -34.985 23.695 ;
        RECT -33.985 22.695 -33.710 23.695 ;
        RECT -35.230 22.535 -33.710 22.695 ;
        RECT -12.680 21.755 -10.750 22.775 ;
        RECT -45.000 15.360 -44.390 16.470 ;
        RECT -36.240 15.360 -35.630 16.470 ;
        RECT -53.440 8.985 -52.830 10.095 ;
        RECT -53.440 6.465 -52.830 7.575 ;
        RECT -43.790 6.660 -42.680 8.890 ;
        RECT -35.030 7.475 -33.920 9.720 ;
        RECT -30.700 8.545 -30.090 9.655 ;
        RECT -45.000 -0.090 -44.390 1.020 ;
        RECT -36.240 -0.090 -35.630 1.020 ;
        RECT -29.840 -0.090 -29.230 16.470 ;
        RECT -12.315 13.335 -11.205 18.395 ;
        RECT -12.315 12.835 -11.955 13.335 ;
        RECT -11.455 12.835 -11.205 13.335 ;
        RECT -12.315 10.220 -11.205 12.835 ;
        RECT -10.190 9.865 -9.320 29.025 ;
        RECT 5.355 21.830 6.875 22.440 ;
        RECT 7.705 21.375 7.905 22.895 ;
        RECT 8.735 21.830 10.255 22.440 ;
        RECT 12.115 21.830 13.635 22.440 ;
        RECT 14.465 21.375 14.665 22.895 ;
        RECT 15.495 21.830 17.015 22.440 ;
        RECT 18.875 21.830 20.395 22.440 ;
        RECT 21.225 21.375 21.425 22.895 ;
        RECT 22.255 21.830 23.775 22.440 ;
        RECT 25.635 21.830 27.155 22.440 ;
        RECT 27.985 21.375 28.185 22.895 ;
        RECT 29.015 21.830 30.535 22.440 ;
        RECT -18.820 7.340 -17.860 9.655 ;
        RECT -18.820 4.465 -18.560 7.340 ;
        RECT -15.640 3.930 -15.350 6.805 ;
        RECT -8.940 5.085 -8.240 5.695 ;
        RECT -23.080 -2.115 -21.970 1.995 ;
        RECT -16.340 0.885 -15.350 3.930 ;
        RECT -23.080 -2.400 -20.280 -2.115 ;
        RECT -23.080 -3.400 -22.745 -2.400 ;
        RECT -22.245 -3.400 -20.280 -2.400 ;
        RECT -23.080 -7.365 -20.280 -3.400 ;
        RECT -7.425 -3.745 -5.995 11.385 ;
        RECT 7.705 9.865 7.905 11.385 ;
        RECT 14.465 9.865 14.665 11.385 ;
        RECT 21.225 9.865 21.425 11.385 ;
        RECT 27.985 9.865 28.185 11.385 ;
        RECT -17.845 -5.735 -5.995 -3.745 ;
        RECT -23.080 -9.450 -21.970 -7.365 ;
        RECT -9.220 -9.445 -8.110 -8.835 ;
        RECT 15.800 -10.225 20.600 -9.615 ;
        RECT 21.980 -10.225 26.780 -9.615 ;
        RECT 28.170 -10.055 32.970 -9.445 ;
        RECT 34.980 -10.065 39.780 -9.455 ;
      LAYER Metal4 ;
        RECT -54.210 54.255 -53.600 59.055 ;
        RECT -41.290 33.085 -40.665 43.980 ;
        RECT -36.250 43.280 -35.640 43.980 ;
        RECT -36.250 40.100 -35.680 43.280 ;
        RECT -36.250 39.600 -36.180 40.100 ;
        RECT -36.250 36.690 -35.680 39.600 ;
        RECT -36.250 35.580 -35.640 36.690 ;
        RECT -41.290 31.980 -34.440 33.085 ;
        RECT -35.050 31.975 -34.440 31.980 ;
        RECT -28.110 27.915 -27.410 43.435 ;
        RECT -19.045 24.260 -18.345 49.315 ;
        RECT -12.080 38.520 92.040 112.305 ;
        RECT -12.080 37.520 40.010 38.520 ;
        RECT 42.010 37.520 92.040 38.520 ;
        RECT -12.080 30.970 92.040 37.520 ;
        RECT -12.970 21.375 31.275 22.895 ;
        RECT -48.475 15.360 -29.230 16.470 ;
        RECT -10.190 10.810 31.275 11.385 ;
        RECT -10.190 10.310 -8.955 10.810 ;
        RECT -7.955 10.310 31.275 10.810 ;
        RECT -53.440 8.985 -52.830 10.095 ;
        RECT -10.190 9.865 31.275 10.310 ;
        RECT -43.790 8.280 -33.920 8.890 ;
        RECT -30.700 8.545 -17.860 9.655 ;
        RECT -53.440 6.465 -52.830 7.575 ;
        RECT -8.940 5.085 -8.240 5.695 ;
        RECT -48.475 -0.090 -29.230 1.020 ;
        RECT -7.255 -5.270 -6.145 -4.250 ;
        RECT 15.800 -10.225 20.600 -9.615 ;
        RECT 21.980 -10.225 26.780 -9.615 ;
        RECT 28.170 -10.055 32.970 -9.445 ;
        RECT 34.980 -10.065 39.780 -9.455 ;
      LAYER Metal5 ;
        RECT -57.140 60.650 44.030 62.290 ;
        RECT -57.140 10.095 -55.500 60.650 ;
        RECT -54.240 54.055 -12.395 59.255 ;
        RECT -57.140 6.465 -52.830 10.095 ;
        RECT -57.140 -10.710 -55.500 6.465 ;
        RECT -8.940 5.080 -8.240 5.700 ;
        RECT -1.635 -3.875 14.565 6.750 ;
        RECT -7.425 -5.605 14.565 -3.875 ;
        RECT -1.635 -9.450 14.565 -5.605 ;
        RECT 15.600 -10.220 20.800 6.750 ;
        RECT 21.780 -10.220 26.980 6.750 ;
        RECT 27.940 -10.085 33.140 6.750 ;
        RECT 34.780 -10.065 39.980 25.830 ;
        RECT 15.800 -10.225 20.600 -10.220 ;
        RECT 21.980 -10.225 26.780 -10.220 ;
        RECT 42.390 -10.710 44.030 60.650 ;
        RECT -57.140 -12.350 44.030 -10.710 ;
      LAYER TopMetal1 ;
        RECT -4.160 66.610 2.895 67.815 ;
        RECT -4.160 65.610 -1.690 66.610 ;
        RECT 0.310 65.610 2.895 66.610 ;
        RECT -4.160 62.290 2.895 65.610 ;
        RECT -57.140 60.650 44.030 62.290 ;
        RECT -57.140 -10.710 -55.500 60.650 ;
        RECT -52.890 54.765 -49.105 60.650 ;
        RECT -46.885 54.765 -43.105 60.650 ;
        RECT -40.885 54.765 -37.105 60.650 ;
        RECT -34.885 54.765 -31.105 60.650 ;
        RECT -28.885 54.765 -25.105 60.650 ;
        RECT -22.885 54.765 -19.105 60.650 ;
        RECT -16.885 54.765 -13.105 60.650 ;
        RECT 42.390 25.120 44.030 60.650 ;
        RECT 35.490 21.340 44.030 25.120 ;
        RECT 42.390 19.120 44.030 21.340 ;
        RECT 35.490 15.340 44.030 19.120 ;
        RECT 42.390 13.120 44.030 15.340 ;
        RECT 35.490 9.340 44.030 13.120 ;
        RECT 42.390 7.120 44.030 9.340 ;
        RECT -9.410 4.570 14.025 6.210 ;
        RECT -1.095 -8.910 14.025 4.570 ;
        RECT 16.310 -10.710 20.090 3.790 ;
        RECT 22.490 -10.710 26.270 3.790 ;
        RECT 28.650 -10.710 32.430 3.790 ;
        RECT 35.490 3.340 44.030 7.120 ;
        RECT 42.390 1.120 44.030 3.340 ;
        RECT 35.490 -2.660 44.030 1.120 ;
        RECT 42.390 -4.880 44.030 -2.660 ;
        RECT 35.490 -8.660 44.030 -4.880 ;
        RECT 42.390 -10.710 44.030 -8.660 ;
        RECT -57.140 -12.350 44.030 -10.710 ;
  END
END bgr_ip
END LIBRARY

